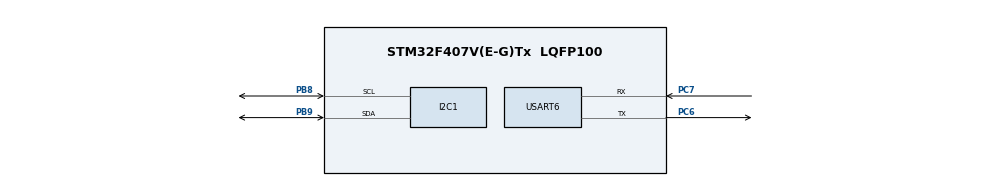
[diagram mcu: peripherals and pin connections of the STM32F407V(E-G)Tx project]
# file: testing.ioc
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Mcu.Family=STM32F4
Mcu.Name=STM32F407V(E-G)Tx
Mcu.Package=LQFP100
NVIC.PriorityGroup=NVIC_PRIORITYGROUP_4
PA13.Mode=JTAG_5_pins
PA13.Signal=SYS_JTMS-SWDIO
PA14.Mode=JTAG_5_pins
PA14.Signal=SYS_JTCK-SWCLK
PA15.Mode=JTAG_5_pins
PA15.Signal=SYS_JTDI
PB3.Mode=JTAG_5_pins
PB3.Signal=SYS_JTDO-SWO
PB4.Mode=JTAG_5_pins
PB4.Signal=SYS_JTRST
PB8.Mode=I2C
PB8.Signal=I2C1_SCL
PB9.Mode=I2C
PB9.Signal=I2C1_SDA
PC6.Mode=Asynchronous
PC6.Signal=USART6_TX
PC7.Mode=Asynchronous
PC7.Signal=USART6_RX
PH0-OSC_IN.Mode=HSE-External-Oscillator
PH0-OSC_IN.Signal=RCC_OSC_IN
PH1-OSC_OUT.Mode=HSE-External-Oscillator
PH1-OSC_OUT.Signal=RCC_OSC_OUT
ProjectManager.HeapSize=0x200
ProjectManager.StackSize=0x400
ProjectManager.TargetToolchain=STM32CubeIDE
RCC.48MHZClocksFreq_Value=84000000
RCC.AHBFreq_Value=168000000
RCC.APB1CLKDivider=RCC_HCLK_DIV4
RCC.APB1Freq_Value=42000000
RCC.APB1TimFreq_Value=84000000
RCC.APB2CLKDivider=RCC_HCLK_DIV2
RCC.APB2Freq_Value=84000000
RCC.APB2TimFreq_Value=168000000
RCC.CortexFreq_Value=168000000
RCC.HCLKFreq_Value=168000000
RCC.HSE_VALUE=25000000
RCC.HSI_VALUE=16000000
RCC.LSE_VALUE=32768
RCC.PLLM=25
RCC.PLLN=336
RCC.PLLSourceVirtual=RCC_PLLSOURCE_HSE
RCC.SYSCLKFreq_VALUE=168000000
RCC.SYSCLKSource=RCC_SYSCLKSOURCE_PLLCLK
RCC.VCOOutputFreq_Value=336000000
TIM2.Period=10
USART6.VirtualMode=VM_ASYNC
VP_TIM2_VS_ClockSourceINT.Mode=Internal
board=custom

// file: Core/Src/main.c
#include "main.h"
#include "i2c.h"
#include "tim.h"
#include "usart.h"
#include "gpio.h"
#include "melody_setting.h"
#include "oled.h"
#include "keyboard.h"
#include "sdk_uart.h"

void SystemClock_Config(void);

void play_symphony( void )
{
	int length_of_melody;

	uint32_t symphony_notes[] = {N_DS5, N_F5, N_G5, N_AS5, N_G5, N_AS5, N_C6, N_DS6, N_F6, N_F6, N_DS6};
	uint32_t symphony_duration[] = {8, 8, 8, 8, 8, 8, 8, 8, 5, 5, 5};
	length_of_melody = sizeof(symphony_notes) / sizeof(uint32_t);

	Melody_Play(symphony_notes, symphony_duration, length_of_melody);
}

void oled_reset(void)
{
	fillOledScreenWithColor(Black);
	set_cursor(0, 0);
	screen_update();
}

void get_timer_array(uint8_t timer_array[2], uint16_t timer) {
	size_t i;

	i = 0;
	while (i < 2)
	{
		if (timer != 0)
			timer_array[i] = timer % 10 + 0x30;
		timer /= 10;
		i++;
	}
}

void oled_print_timer(uint16_t timer)
{
	uint8_t i = 0;
    uint8_t timer_array[2] = {0, 0};

    if ((timer + 1) % 10 == 0)
        oled_reset();
    set_cursor(60, 28);
    if (timer == 0)
    	write_char('0', Font_7x10, White);
    else
    {
    	get_timer_array(timer_array, timer);
    	while (i < 2) {
			if (timer_array[1 - i] != 0) {
				write_char(timer_array[1 - i], Font_7x10, White);
			}
			i++;
		}
    }
    screen_update();
}

void start_timer( void )
{
	int is_button_pusshed;
	uint8_t i;
	uint16_t timer;
	uint8_t button;
	uint8_t Row[4] = {ROW4, ROW3, ROW2, ROW1};

	UART_Transmit( (uint8_t*)"Start keyboard\n" );
	oled_reset();
	string_write("Enter value:", Font_7x10, White);
	screen_update();

	is_button_pusshed = 0;
	timer = 0;
	while (!is_button_pusshed)
	{
		i = 0;
		while (i < 4)
		{
			button = check_nrow(Row[i]);
			if (button == 0xC)
			{
				timer /= 10;
				oled_reset();
				string_write("Enter value:", Font_7x10, White);
				oled_print_timer(timer);
				HAL_Delay(100);
			}
			else if (button == 0xB && timer < 10)
			{
				timer = timer * 10;
				oled_print_timer(timer);
				HAL_Delay(100);
			}
			else if (button == 0xA)
			{
				is_button_pusshed = 1;
				oled_print_timer(timer);
				break;
			}
			else if (button != 0 && timer < 10)
			{
				timer = timer * 10 + button;
				oled_print_timer(timer);
				HAL_Delay(100);
			}
			i++;
		}
	}
	oled_reset();
	while (timer > 0)
	{
		oled_print_timer(timer);
		HAL_Delay(1000);
		timer -= 1;
	}
	oled_print_timer(0);
	HAL_Delay(1000);

	oled_reset();
	set_cursor(0, 15);
	string_write("I just wanna be", Font_7x10, White);
	set_cursor(0, 25);
	string_write("a part of your", Font_7x10, White);
	set_cursor(0, 35);
	string_write("symphony", Font_7x10, White);
	screen_update();
	play_symphony();
	oled_reset();
}

int main(void)
{
	HAL_Init();
	SystemClock_Config();

	MX_GPIO_Init();
	MX_TIM2_Init();
	MX_I2C1_Init();
	MX_USART6_UART_Init();

	oled_Start();
	Melody_Init();

	while (1)
	{
		start_timer();
		HAL_Delay(500);
	}
}

void SystemClock_Config(void)
{
  RCC_OscInitTypeDef RCC_OscInitStruct = {0};
  RCC_ClkInitTypeDef RCC_ClkInitStruct = {0};

  /** Configure the main internal regulator output voltage
  */
  __HAL_RCC_PWR_CLK_ENABLE();
  __HAL_PWR_VOLTAGESCALING_CONFIG(PWR_REGULATOR_VOLTAGE_SCALE1);

  /** Initializes the RCC Oscillators according to the specified parameters
  * in the RCC_OscInitTypeDef structure.
  */
  RCC_OscInitStruct.OscillatorType = RCC_OSCILLATORTYPE_HSI;
  RCC_OscInitStruct.HSIState = RCC_HSI_ON;
  RCC_OscInitStruct.HSICalibrationValue = RCC_HSICALIBRATION_DEFAULT;
  RCC_OscInitStruct.PLL.PLLState = RCC_PLL_NONE;
  if (HAL_RCC_OscConfig(&RCC_OscInitStruct) != HAL_OK)
  {
    Error_Handler();
  }

  /** Initializes the CPU, AHB and APB buses clocks
  */
  RCC_ClkInitStruct.ClockType = RCC_CLOCKTYPE_HCLK|RCC_CLOCKTYPE_SYSCLK
                              |RCC_CLOCKTYPE_PCLK1|RCC_CLOCKTYPE_PCLK2;
  RCC_ClkInitStruct.SYSCLKSource = RCC_SYSCLKSOURCE_HSI;
  RCC_ClkInitStruct.AHBCLKDivider = RCC_SYSCLK_DIV1;
  RCC_ClkInitStruct.APB1CLKDivider = RCC_HCLK_DIV1;
  RCC_ClkInitStruct.APB2CLKDivider = RCC_HCLK_DIV1;

  if (HAL_RCC_ClockConfig(&RCC_ClkInitStruct, FLASH_LATENCY_0) != HAL_OK)
  {
    Error_Handler();
  }
}

void Error_Handler(void)
{
  __disable_irq();
  while (1)
  {
  }
}
